One B-rep face of a CAD part: STEP entity #36378.
In plain terms, the planar face has unit normal (0, 0, 1).
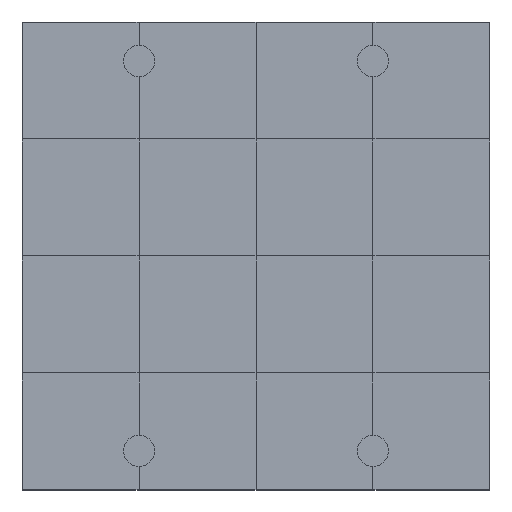
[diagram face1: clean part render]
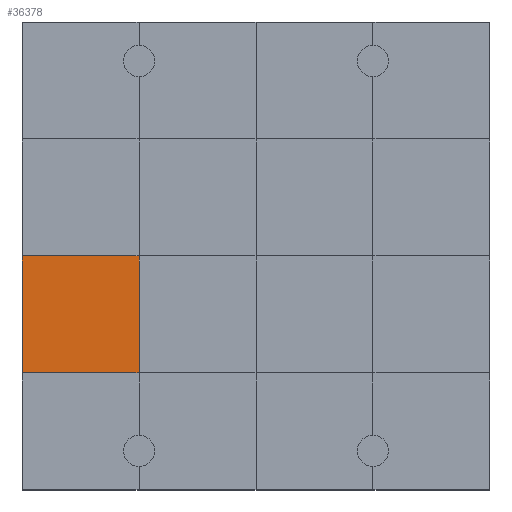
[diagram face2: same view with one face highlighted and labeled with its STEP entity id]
Its self-contained STEP definition (entity closure, numbers rounded to 3 decimals):
#35928 = VERTEX_POINT('',#35929);
#35929 = CARTESIAN_POINT('',(0.,3.,1.2));
#35943 = PLANE('',#35944);
#35944 = AXIS2_PLACEMENT_3D('',#35945,#35946,#35947);
#35945 = CARTESIAN_POINT('',(0.,3.,0.));
#35946 = DIRECTION('',(1.,0.,-0.));
#35947 = DIRECTION('',(0.,0.,1.));
#35969 = PLANE('',#35970);
#35970 = AXIS2_PLACEMENT_3D('',#35971,#35972,#35973);
#35971 = CARTESIAN_POINT('',(0.,0.,1.2));
#35972 = DIRECTION('',(0.,0.,1.));
#35973 = DIRECTION('',(1.,0.,-0.));
#36120 = VERTEX_POINT('',#36121);
#36121 = CARTESIAN_POINT('',(3.,3.,1.2));
#36142 = EDGE_CURVE('',#35928,#36120,#36143,.T.);
#36143 = SURFACE_CURVE('',#36144,(#36148,#36155),.PCURVE_S1.);
#36144 = LINE('',#36145,#36146);
#36145 = CARTESIAN_POINT('',(0.,3.,1.2));
#36146 = VECTOR('',#36147,1.);
#36147 = DIRECTION('',(1.,0.,-0.));
#36148 = PCURVE('',#35969,#36149);
#36149 = DEFINITIONAL_REPRESENTATION('',(#36150),#36154);
#36150 = LINE('',#36151,#36152);
#36151 = CARTESIAN_POINT('',(0.,3.));
#36152 = VECTOR('',#36153,1.);
#36153 = DIRECTION('',(1.,0.));
#36154 = ( GEOMETRIC_REPRESENTATION_CONTEXT(2) 
PARAMETRIC_REPRESENTATION_CONTEXT() REPRESENTATION_CONTEXT('2D SPACE',''
  ) );
#36155 = PCURVE('',#36156,#36161);
#36156 = PLANE('',#36157);
#36157 = AXIS2_PLACEMENT_3D('',#36158,#36159,#36160);
#36158 = CARTESIAN_POINT('',(0.,3.,1.2));
#36159 = DIRECTION('',(0.,0.,1.));
#36160 = DIRECTION('',(1.,0.,-0.));
#36161 = DEFINITIONAL_REPRESENTATION('',(#36162),#36166);
#36162 = LINE('',#36163,#36164);
#36163 = CARTESIAN_POINT('',(0.,0.));
#36164 = VECTOR('',#36165,1.);
#36165 = DIRECTION('',(1.,0.));
#36166 = ( GEOMETRIC_REPRESENTATION_CONTEXT(2) 
PARAMETRIC_REPRESENTATION_CONTEXT() REPRESENTATION_CONTEXT('2D SPACE',''
  ) );
#36201 = VERTEX_POINT('',#36202);
#36202 = CARTESIAN_POINT('',(0.,6.,1.2));
#36228 = EDGE_CURVE('',#35928,#36201,#36229,.T.);
#36229 = SURFACE_CURVE('',#36230,(#36234,#36241),.PCURVE_S1.);
#36230 = LINE('',#36231,#36232);
#36231 = CARTESIAN_POINT('',(0.,3.,1.2));
#36232 = VECTOR('',#36233,1.);
#36233 = DIRECTION('',(-0.,1.,0.));
#36234 = PCURVE('',#35943,#36235);
#36235 = DEFINITIONAL_REPRESENTATION('',(#36236),#36240);
#36236 = LINE('',#36237,#36238);
#36237 = CARTESIAN_POINT('',(1.2,0.));
#36238 = VECTOR('',#36239,1.);
#36239 = DIRECTION('',(0.,-1.));
#36240 = ( GEOMETRIC_REPRESENTATION_CONTEXT(2) 
PARAMETRIC_REPRESENTATION_CONTEXT() REPRESENTATION_CONTEXT('2D SPACE',''
  ) );
#36241 = PCURVE('',#36156,#36242);
#36242 = DEFINITIONAL_REPRESENTATION('',(#36243),#36247);
#36243 = LINE('',#36244,#36245);
#36244 = CARTESIAN_POINT('',(0.,0.));
#36245 = VECTOR('',#36246,1.);
#36246 = DIRECTION('',(0.,1.));
#36247 = ( GEOMETRIC_REPRESENTATION_CONTEXT(2) 
PARAMETRIC_REPRESENTATION_CONTEXT() REPRESENTATION_CONTEXT('2D SPACE',''
  ) );
#36378 = ADVANCED_FACE('',(#36379),#36156,.T.);
#36379 = FACE_BOUND('',#36380,.T.);
#36380 = EDGE_LOOP('',(#36381,#36382,#36383,#36411));
#36381 = ORIENTED_EDGE('',*,*,#36228,.F.);
#36382 = ORIENTED_EDGE('',*,*,#36142,.T.);
#36383 = ORIENTED_EDGE('',*,*,#36384,.T.);
#36384 = EDGE_CURVE('',#36120,#36385,#36387,.T.);
#36385 = VERTEX_POINT('',#36386);
#36386 = CARTESIAN_POINT('',(3.,6.,1.2));
#36387 = SURFACE_CURVE('',#36388,(#36392,#36399),.PCURVE_S1.);
#36388 = LINE('',#36389,#36390);
#36389 = CARTESIAN_POINT('',(3.,3.,1.2));
#36390 = VECTOR('',#36391,1.);
#36391 = DIRECTION('',(-0.,1.,0.));
#36392 = PCURVE('',#36156,#36393);
#36393 = DEFINITIONAL_REPRESENTATION('',(#36394),#36398);
#36394 = LINE('',#36395,#36396);
#36395 = CARTESIAN_POINT('',(3.,0.));
#36396 = VECTOR('',#36397,1.);
#36397 = DIRECTION('',(0.,1.));
#36398 = ( GEOMETRIC_REPRESENTATION_CONTEXT(2) 
PARAMETRIC_REPRESENTATION_CONTEXT() REPRESENTATION_CONTEXT('2D SPACE',''
  ) );
#36399 = PCURVE('',#36400,#36405);
#36400 = PLANE('',#36401);
#36401 = AXIS2_PLACEMENT_3D('',#36402,#36403,#36404);
#36402 = CARTESIAN_POINT('',(3.,3.,1.2));
#36403 = DIRECTION('',(0.,0.,1.));
#36404 = DIRECTION('',(1.,0.,-0.));
#36405 = DEFINITIONAL_REPRESENTATION('',(#36406),#36410);
#36406 = LINE('',#36407,#36408);
#36407 = CARTESIAN_POINT('',(0.,0.));
#36408 = VECTOR('',#36409,1.);
#36409 = DIRECTION('',(0.,1.));
#36410 = ( GEOMETRIC_REPRESENTATION_CONTEXT(2) 
PARAMETRIC_REPRESENTATION_CONTEXT() REPRESENTATION_CONTEXT('2D SPACE',''
  ) );
#36411 = ORIENTED_EDGE('',*,*,#36412,.F.);
#36412 = EDGE_CURVE('',#36201,#36385,#36413,.T.);
#36413 = SURFACE_CURVE('',#36414,(#36418,#36425),.PCURVE_S1.);
#36414 = LINE('',#36415,#36416);
#36415 = CARTESIAN_POINT('',(0.,6.,1.2));
#36416 = VECTOR('',#36417,1.);
#36417 = DIRECTION('',(1.,0.,-0.));
#36418 = PCURVE('',#36156,#36419);
#36419 = DEFINITIONAL_REPRESENTATION('',(#36420),#36424);
#36420 = LINE('',#36421,#36422);
#36421 = CARTESIAN_POINT('',(0.,3.));
#36422 = VECTOR('',#36423,1.);
#36423 = DIRECTION('',(1.,0.));
#36424 = ( GEOMETRIC_REPRESENTATION_CONTEXT(2) 
PARAMETRIC_REPRESENTATION_CONTEXT() REPRESENTATION_CONTEXT('2D SPACE',''
  ) );
#36425 = PCURVE('',#36426,#36431);
#36426 = PLANE('',#36427);
#36427 = AXIS2_PLACEMENT_3D('',#36428,#36429,#36430);
#36428 = CARTESIAN_POINT('',(0.,6.,1.2));
#36429 = DIRECTION('',(0.,0.,1.));
#36430 = DIRECTION('',(1.,0.,-0.));
#36431 = DEFINITIONAL_REPRESENTATION('',(#36432),#36436);
#36432 = LINE('',#36433,#36434);
#36433 = CARTESIAN_POINT('',(0.,0.));
#36434 = VECTOR('',#36435,1.);
#36435 = DIRECTION('',(1.,0.));
#36436 = ( GEOMETRIC_REPRESENTATION_CONTEXT(2) 
PARAMETRIC_REPRESENTATION_CONTEXT() REPRESENTATION_CONTEXT('2D SPACE',''
  ) );
